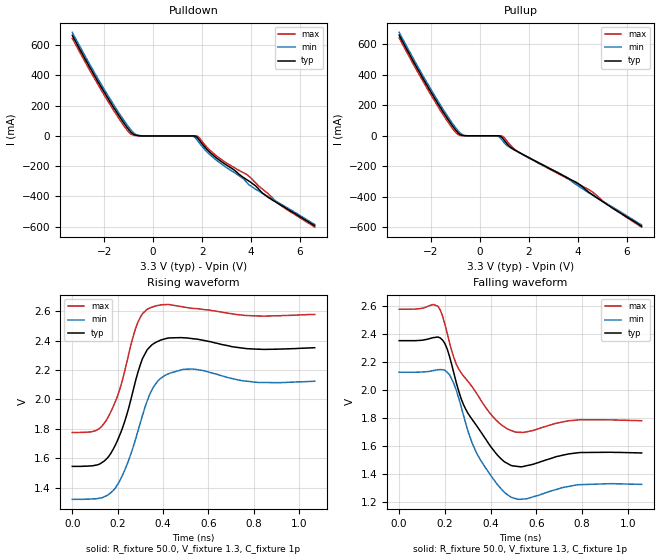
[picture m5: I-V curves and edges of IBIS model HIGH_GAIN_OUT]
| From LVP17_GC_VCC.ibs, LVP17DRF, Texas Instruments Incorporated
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|   Driver Output Model
[Model]   HIGH_GAIN_OUT
Model_type   Output_ECL
| Signals   Y,Z
Vmeas = 2.0V   |Reference voltage for timing measurements
Cref = 0pF   |Timing specification test load capacitance value
Rref = 50
|Note: 50 Ohm load; single ended configuration
| variable   typ   min   max
C_comp   0.8pF   0.6pF   0.9pF
|   typ   min   max
[Temperature Range]   25   -40   85
[Voltage range]   3.3V   3.0V   3.6V
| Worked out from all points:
|   rising waveform, R_fixture 50.0, V_fixture 1.3, C_fixture 1p: 20-80 % time 95.7ps typ, 104ps min, 90.8ps max; typ from 1.54 V to 2.35 V
|   falling waveform, R_fixture 50.0, V_fixture 1.3, C_fixture 1p: 20-80 % time 125ps typ, 105ps min, 144ps max; typ from 2.35 V to 1.55 V
[Pulldown]
|Voltage I(typ)   I(min)   I(max)
| Note that the[Pulldown]voltage table for (P)ECL is referenced
| to Vcc and is calculated using Vtable=Vcc - Vmeasured.
-3.3V     665mA      685mA      645mA
-1.6V     185mA      204mA      166mA
-1V       43mA       59.7mA     26.4mA
-800mV    10.5mA     21.4mA     5.1mA
-400mV    4.63uA     184uA      6.49nA
1.6V      -13.8uA    -610uA     -49.5nA
1.8V      -9.83mA    -27mA      -827uA
2.6V      -147mA     -162mA     -133mA
3.7V      -276mA     -285mA     -244mA
3.9V      -297mA     -321mA     -264mA
5.1V      -446mA     -439mA     -446mA
6.6V      -594mA     -585mA     -603mA
[Pullup]
|Voltage   I(typ)   I(min)   I(max)
| Note that the[Pullup]voltage table is referenced to Vcc
| and is calculated using Vtable=Vcc - Vmeasured.
-3.3V     660mA      678mA      641mA
-1.6V     181mA      198mA      162mA
-1V       38.9mA     54.4mA     22.9mA
-800mV    6.8mA      16.6mA     2.2mA
-600mV    174uA      993uA      1.73uA
700mV     -17.7uA    -731uA     -46.4nA
900mV     -10.8mA    -27.6mA    -775uA
1.2V      -69.4mA    -74.7mA    -54.2mA
1.5V      -100mA     -101mA     -99.8mA
3.5V      -270mA     -268mA     -275mA
4.5V      -376mA     -380mA     -358mA
6.6V      -593mA     -585mA     -599mA
[Ramp]
|   typ   min   max
dV/dt_r   0.484/92ps   0.482/105ps   0.481/90ps
dV/dt_f   0.482/90ps   0.482/105ps   0.479/145ps
R_load = 50ohm  |Note: The measurement is with 50ohm to Vtt.
[Rising Waveform]
R_fixture = 50.0
V_fixture = 1.3
V_fixture_min = 1.0
V_fixture_max = 1.6
C_fixture = 1p
L_fixture = 0n
|   V(typ)  V(min)  V(max)
0s        1.545V     1.321V     1.775V
120ps     1.56V      1.329V     1.803V
190ps     1.689V     1.398V     1.985V
240ps     1.893V     1.551V     2.248V
280ps     2.131V     1.733V     2.485V
340ps     2.353V     2.028V     2.62V
390ps     2.403V     2.143V     2.642V
490ps     2.419V     2.204V     2.628V
820ps     2.341V     2.115V     2.567V
1.07ns    2.351V     2.124V     2.577V
[Falling Waveform]
R_fixture = 50.0
V_fixture = 1.3
V_fixture_min = 1.0
V_fixture_max = 1.6
C_fixture = 1p
L_fixture = 0n
|   V(typ)  V(min)  V(max)
0s        2.352V     2.126V     2.577V
170ps     2.378V     2.144V     2.598V
220ps     2.24V      2.11V      2.339V
250ps     2.05V      1.996V     2.183V
280ps     1.899V     1.825V     2.102V
340ps     1.74V      1.543V     1.971V
410ps     1.573V     1.365V     1.807V
490ps     1.458V     1.231V     1.709V
790ps     1.551V     1.321V     1.786V
1.06ns    1.548V     1.323V     1.779V
